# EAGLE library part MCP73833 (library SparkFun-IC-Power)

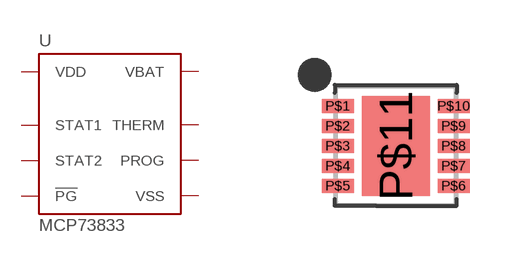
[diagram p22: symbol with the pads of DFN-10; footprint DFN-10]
Designator prefix U

## MCP73833 (PROD_ID: IC-14369; VALUE: MCP73833)  [DFN-10]
P$1  VDD
P$2  VDD
P$3  STAT1
P$4  STAT2
P$5  VSS
P$6  PROG
P$7  !PG
P$8  THERM
P$9  VBAT
P$10  VBAT
P$11  VSS

## Footprint DFN-10 (pad centres in mm)
smd 0.8 x 0.35: P$1 -1.45,1; P$2 -1.45,0.5; P$3 -1.45,0; P$4 -1.45,-0.5; P$5 -1.45,-1; P$6 1.45,-1; P$7 1.45,-0.5; P$8 1.45,0; P$9 1.45,0.5; P$10 1.45,1
smd 1.7 x 2.5: P$11 0,0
